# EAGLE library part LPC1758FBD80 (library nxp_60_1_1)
LPC1758 100 MHz 32-bit ARM Cortex-M3 based microcontroller featuring a high level of integration and low power consumption. 512 kB Flash, 64 kB SRAM, USB Device/Host/OTG, 2 CAN, DAC, Ethernet MarcVl - Datasheet available on www.nxp.com

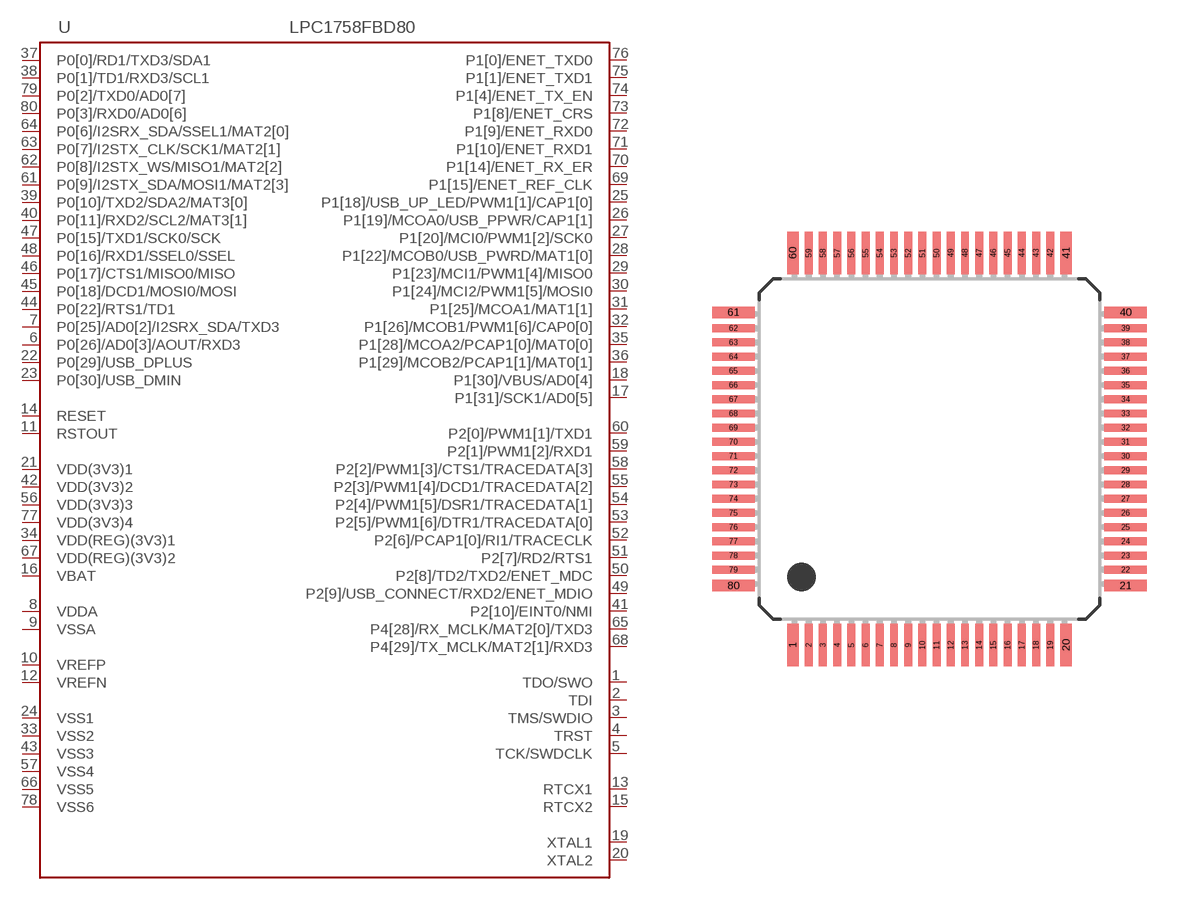
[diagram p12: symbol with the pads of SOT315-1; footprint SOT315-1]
Designator prefix U

## LPC1758FBD80  [SOT315-1]
1  TDO/SWO  out
2  TDI  in
3  TMS/SWDIO
4  TRST
5  TCK/SWDCLK
6  P0[26]/AD0[3]/AOUT/RXD3
7  P0[25]/AD0[2]/I2SRX_SDA/TXD3
8  VDDA  pwr
9  VSSA  pwr
10  VREFP  in
11  RSTOUT  out
12  VREFN  in
13  RTCX1  in
14  RESET  in
15  RTCX2  out
16  VBAT  pwr
17  P1[31]/SCK1/AD0[5]
18  P1[30]/VBUS/AD0[4]
19  XTAL1  in
20  XTAL2  out
21  VDD(3V3)1  pwr
22  P0[29]/USB_DPLUS
23  P0[30]/USB_DMIN
24  VSS1  pwr
25  P1[18]/USB_UP_LED/PWM1[1]/CAP1[0]
26  P1[19]/MCOA0/USB_PPWR/CAP1[1]
27  P1[20]/MCI0/PWM1[2]/SCK0
28  P1[22]/MCOB0/USB_PWRD/MAT1[0]
29  P1[23]/MCI1/PWM1[4]/MISO0
30  P1[24]/MCI2/PWM1[5]/MOSI0
31  P1[25]/MCOA1/MAT1[1]
32  P1[26]/MCOB1/PWM1[6]/CAP0[0]
33  VSS2  pwr
34  VDD(REG)(3V3)1  pwr
35  P1[28]/MCOA2/PCAP1[0]/MAT0[0]
36  P1[29]/MCOB2/PCAP1[1]/MAT0[1]
37  P0[0]/RD1/TXD3/SDA1
38  P0[1]/TD1/RXD3/SCL1
39  P0[10]/TXD2/SDA2/MAT3[0]
40  P0[11]/RXD2/SCL2/MAT3[1]
41  P2[10]/EINT0/NMI
42  VDD(3V3)2  pwr
43  VSS3  pwr
44  P0[22]/RTS1/TD1
45  P0[18]/DCD1/MOSI0/MOSI
46  P0[17]/CTS1/MISO0/MISO
47  P0[15]/TXD1/SCK0/SCK
48  P0[16]/RXD1/SSEL0/SSEL
49  P2[9]/USB_CONNECT/RXD2/ENET_MDIO
50  P2[8]/TD2/TXD2/ENET_MDC
51  P2[7]/RD2/RTS1
52  P2[6]/PCAP1[0]/RI1/TRACECLK
53  P2[5]/PWM1[6]/DTR1/TRACEDATA[0]
54  P2[4]/PWM1[5]/DSR1/TRACEDATA[1]
55  P2[3]/PWM1[4]/DCD1/TRACEDATA[2]
56  VDD(3V3)3  pwr
57  VSS4  pwr
58  P2[2]/PWM1[3]/CTS1/TRACEDATA[3]
59  P2[1]/PWM1[2]/RXD1
60  P2[0]/PWM1[1]/TXD1
61  P0[9]/I2STX_SDA/MOSI1/MAT2[3]
62  P0[8]/I2STX_WS/MISO1/MAT2[2]
63  P0[7]/I2STX_CLK/SCK1/MAT2[1]
64  P0[6]/I2SRX_SDA/SSEL1/MAT2[0]
65  P4[28]/RX_MCLK/MAT2[0]/TXD3
66  VSS5  pwr
67  VDD(REG)(3V3)2  pwr
68  P4[29]/TX_MCLK/MAT2[1]/RXD3
69  P1[15]/ENET_REF_CLK
70  P1[14]/ENET_RX_ER
71  P1[10]/ENET_RXD1
72  P1[9]/ENET_RXD0
73  P1[8]/ENET_CRS
74  P1[4]/ENET_TX_EN
75  P1[1]/ENET_TXD1
76  P1[0]/ENET_TXD0
77  VDD(3V3)4  pwr
78  VSS6  pwr
79  P0[2]/TXD0/AD0[7]
80  P0[3]/RXD0/AD0[6]

## Footprint SOT315-1 (pad centres in mm)
SOT315-1 LQFP80: plastic low profile quad flat package; 80 leads; body 12 x 12 x 1.4 mm JEDEC: MS-026 IEC: 136E15
smd 0.4 x 1.5: 1 -4.81,-6.9; 20 4.81,-6.9; 41 4.81,6.9; 60 -4.81,6.9
smd 0.28 x 1.5: 2 -4.25,-6.9; 3 -3.75,-6.9; 4 -3.25,-6.9; 5 -2.75,-6.9; 6 -2.25,-6.9; 7 -1.75,-6.9; 8 -1.25,-6.9; 9 -0.75,-6.9; 10 -0.25,-6.9; 11 0.25,-6.9; 12 0.75,-6.9; 13 1.25,-6.9; 14 1.75,-6.9; 15 2.25,-6.9; 16 2.75,-6.9; 17 3.25,-6.9; 18 3.75,-6.9; 19 4.25,-6.9; 42 4.25,6.9; 43 3.75,6.9; 44 3.25,6.9; 45 2.75,6.9; 46 2.25,6.9; 47 1.75,6.9; 48 1.25,6.9; 49 0.75,6.9; 50 0.25,6.9; 51 -0.25,6.9; 52 -0.75,6.9; 53 -1.25,6.9; 54 -1.75,6.9; 55 -2.25,6.9; 56 -2.75,6.9; 57 -3.25,6.9; 58 -3.75,6.9; 59 -4.25,6.9
smd 1.5 x 0.4: 21 6.9,-4.81; 40 6.9,4.81; 61 -6.9,4.81; 80 -6.9,-4.81
smd 1.5 x 0.28: 22 6.9,-4.25; 23 6.9,-3.75; 24 6.9,-3.25; 25 6.9,-2.75; 26 6.9,-2.25; 27 6.9,-1.75; 28 6.9,-1.25; 29 6.9,-0.75; 30 6.9,-0.25; 31 6.9,0.25; 32 6.9,0.75; 33 6.9,1.25; 34 6.9,1.75; 35 6.9,2.25; 36 6.9,2.75; 37 6.9,3.25; 38 6.9,3.75; 39 6.9,4.25; 62 -6.9,4.25; 63 -6.9,3.75; 64 -6.9,3.25; 65 -6.9,2.75; 66 -6.9,2.25; 67 -6.9,1.75; 68 -6.9,1.25; 69 -6.9,0.75; 70 -6.9,0.25; 71 -6.9,-0.25; 72 -6.9,-0.75; 73 -6.9,-1.25; 74 -6.9,-1.75; 75 -6.9,-2.25; 76 -6.9,-2.75; 77 -6.9,-3.25; 78 -6.9,-3.75; 79 -6.9,-4.25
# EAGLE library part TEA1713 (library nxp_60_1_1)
Resonant power supply control IC with PFC. AAL Eindhoven MK

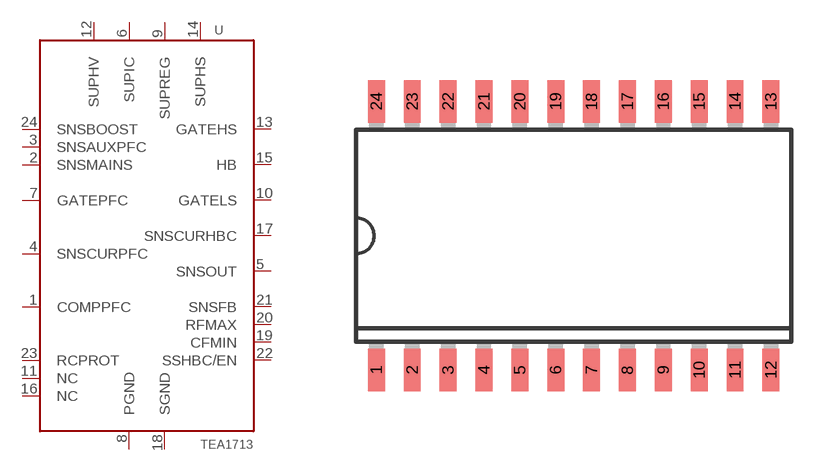
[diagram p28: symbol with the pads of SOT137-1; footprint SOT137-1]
Designator prefix U

## TEA1713T (12NC: 9352 895 98518; FARNELL: 1872212)  [SOT137-1]
1  COMPPFC  pas
2  SNSMAINS  pas
3  SNSAUXPFC  pas
4  SNSCURPFC  pas
5  SNSOUT  out
6  SUPIC  pwr
7  GATEPFC  out
8  PGND  pwr
9  SUPREG  pas
10  GATELS  out
11  NC  out
12  SUPHV  in
13  GATEHS  out
14  SUPHS  in
15  HB  in
16  NC  out
17  SNSCURHBC  out
18  SGND  pwr
19  CFMIN  pas
20  RFMAX  pas
21  SNSFB  in
22  SSHBC/EN  in
23  RCPROT  pas
24  SNSBOOST  in

## Footprint SOT137-1 (pad centres in mm)
SOT137-1 SO24: plastic small outline package; 24 leads; body width 7.5 mm JEDEC: MS-013 IEC: 075E05
smd 0.6 x 1.5: 1 -6.985,-4.75; 2 -5.715,-4.75; 3 -4.445,-4.75; 4 -3.175,-4.75; 5 -1.905,-4.75; 6 -0.635,-4.75; 7 0.635,-4.75; 8 1.905,-4.75; 9 3.175,-4.75; 10 4.445,-4.75; 11 5.715,-4.75; 12 6.985,-4.75; 13 6.985,4.75; 14 5.715,4.75; 15 4.445,4.75; 16 3.175,4.75; 17 1.905,4.75; 18 0.635,4.75; 19 -0.635,4.75; 20 -1.905,4.75; 21 -3.175,4.75; 22 -4.445,4.75; 23 -5.715,4.75; 24 -6.985,4.75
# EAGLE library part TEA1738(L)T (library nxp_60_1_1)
The TEA1738(T) is a low cost Switched Mode Power Supply (SMPS) controller IC intended for flyback topologies. The TEA1738(T) operates in peak current and frequency control mode. To reduce Electro Magnetic Interference (EMI), frequency jitter has been implemented. Slope compensation is integrated for Continuous Conduction Mode (CCM) operation. AAL Eindhoven MK

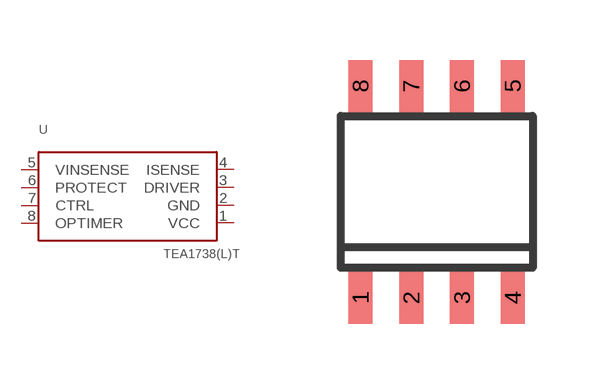
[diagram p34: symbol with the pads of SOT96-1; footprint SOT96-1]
Designator prefix U

## TEA1738(L)T (12NC: 9352 918 76118)  [SOT96-1]
1  VCC  pwr
2  GND  pwr
3  DRIVER  out
4  ISENSE  in
5  VINSENSE  in
6  PROTECT  in
7  CTRL  in
8  OPTIMER  pas

## Footprint SOT96-1 (pad centres in mm)
SOT96-1 SO8: plastic small outline package; 8 leads; body width 3.9 mm JEDEC: MS-012 IEC: 076E03
smd 0.6 x 1.3: 1 -1.905,-2.65; 2 -0.635,-2.65; 3 0.635,-2.65; 4 1.905,-2.65; 5 1.905,2.65; 6 0.635,2.65; 7 -0.635,2.65; 8 -1.905,2.65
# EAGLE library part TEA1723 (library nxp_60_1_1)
Switch mode power supply controller AAL Eindhoven MK

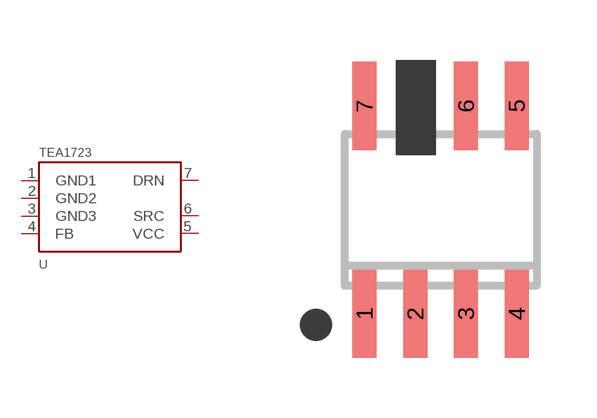
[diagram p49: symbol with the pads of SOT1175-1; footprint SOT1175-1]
Designator prefix U

## TEA1723 (12NC: 9352 968 88118)  [SOT1175-1]
1  GND1  pwr
2  GND2  pwr
3  GND3  pwr
4  FB
5  VCC  pwr
6  SRC  in
7  DRN  out

## Footprint SOT1175-1 (pad centres in mm)
SOT1175-1 SO7: plastic small outline package; 7 leads; body width 3.9 m JEDEC: --- IEC: ---
smd 0.6 x 2.2: 1 -1.905,-2.6; 2 -0.635,-2.6; 3 0.635,-2.6; 4 1.905,-2.6; 5 1.905,2.6; 6 0.635,2.6; 7 -1.905,2.6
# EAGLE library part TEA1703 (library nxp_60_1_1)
GreenChip SMPS standby control IC

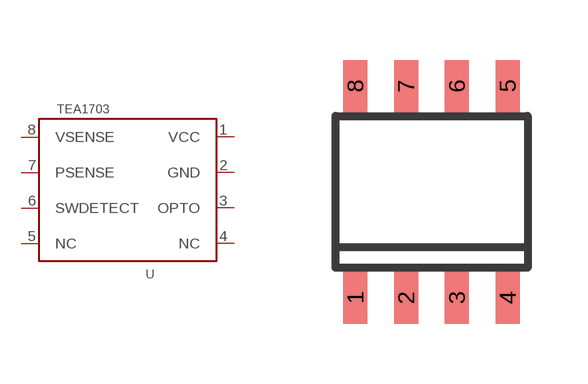
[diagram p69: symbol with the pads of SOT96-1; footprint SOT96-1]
Designator prefix U

## TEA1703  [SOT96-1]
1  VCC  pwr
2  GND  pwr
3  OPTO  out
4  NC  in
5  NC  in
6  SWDETECT  pas
7  PSENSE  pas
8  VSENSE  pas

## Footprint SOT96-1 (pad centres in mm)
SOT96-1 SO8: plastic small outline package; 8 leads; body width 3.9 mm JEDEC: MS-012 IEC: 076E03
smd 0.6 x 1.3: 1 -1.905,-2.65; 2 -0.635,-2.65; 3 0.635,-2.65; 4 1.905,-2.65; 5 1.905,2.65; 6 0.635,2.65; 7 -0.635,2.65; 8 -1.905,2.65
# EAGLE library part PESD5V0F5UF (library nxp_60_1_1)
Femtofarad unidirectional fivefold ESD protection array Femtofarad capacitance unidirectional ElectroStatic Discharge (ESD) protection diode array designed to protect up to five signal lines from the damage caused by ESD and other transients. The device is encapsulated in a leadless ultra small DFN1410-6 (SOT886) Surface-Mounted Device (SMD) plastic package. The combination of extremely low capacitance, high ESD maximum rating and ultra small package makes the device ideal for high-speed data line protection and antenna protection applications. AAL Eindhoven MK

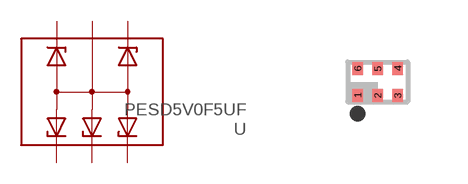
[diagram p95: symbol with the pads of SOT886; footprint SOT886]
Designator prefix U

## PESD5V0F5UF  [SOT886]
1  1  pas
2  2  pas
3  3  pas
4  4  pas
5  5  pas
6  6  pas

## Footprint SOT886 (pad centres in mm)
SOT886 XSON6: plastic extremely thin small outline package; no leads; 6 terminals; body 1 x 1.45 x 0.5 mm JEDEC: MO-252 IEC: ---
smd 0.27 x 0.325: 1 -0.5,-0.338; 2 0,-0.338; 3 0.5,-0.338; 4 0.5,0.338; 5 0,0.338; 6 -0.5,0.338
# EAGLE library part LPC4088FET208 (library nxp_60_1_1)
32-bit ARM Cortex-M4 MCU; up to 512 kB flash, 96 kB SRAM; USB Device/Host/OTG; Ethernet; LCD; EMC; SPIFI The LPC408x/7x is an ARM Cortex-M4 based digital signal controller for embedded applications requiring a high level of integration and low power dissipation. The ARM Cortex-M4 is a next generation core that offers system enhancements such as low power consumption, enhanced debug features, and a high level of support block integration. The ARM Cortex-M4 CPU incorporates a 3-stage pipeline, uses a Harvard architecture with separate local instruction and data buses as well as a third bus for peripherals, and includes an internal prefetch unit that supports speculative branching. The ARM Cortex-M4 supports single-cycle digital signal processing and SIMD instructions. A hardware floating-point processor is integrated in the core for several versions of the part. The LPC408x/7x adds a specialized flash memory accelerator to accomplish optimal performance when executing code from flash. The LPC408x/7x is targeted to operate at up to 120 MHz CPU frequency. The peripheral complement of the LPC408x/7x includes up to 512 kB of flash program memory, up to 96 kB of SRAM data memory, up to 4032 byte of EEPROM data memory, External Memory controller (EMC), LCD, Ethernet, USB Device/Host/OTG, an SPI Flash Interface (SPIFI), a General Purpose DMA controller, five UARTs, three SSP controllers, three I 2 C-bus interfaces, a Quadrature Encoder Interface, four general purpose timers, two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

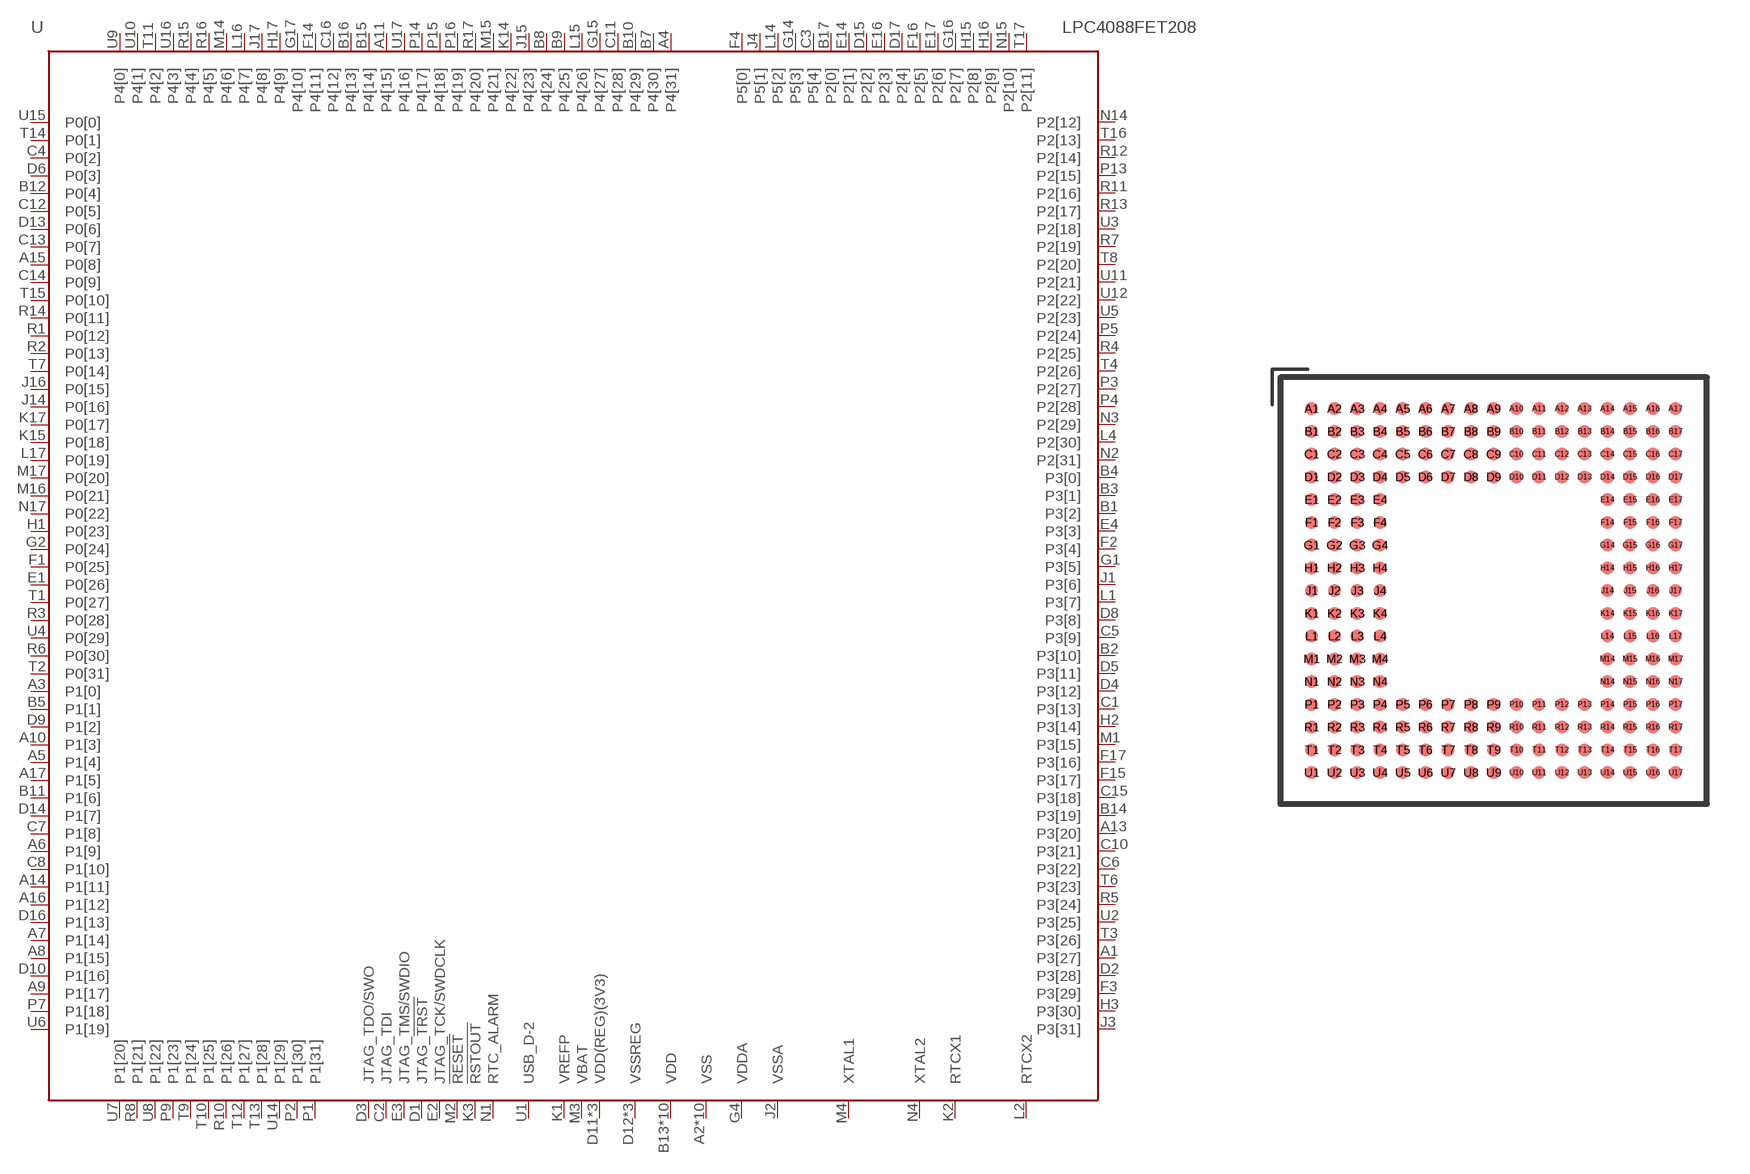
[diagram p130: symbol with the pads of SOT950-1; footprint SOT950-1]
Designator prefix U

## LPC4088FET208  [SOT950-1]
A1  P3[27]
A2  VSS  pwr
A3  P1[0]
A4  P4[31]
A5  P1[4]
A6  P1[9]
A7  P1[14]
A8  P1[15]
A9  P1[17]
A10  P1[3]
A11  P4[15]
A12  VSS  pwr
A13  P3[20]
A14  P1[11]
A15  P0[8]
A16  P1[12]
A17  P1[5]
B1  P3[2]
B2  P3[10]
B3  P3[1]
B4  P3[0]
B5  P1[1]
B6  VSS  pwr
B7  P4[30]
B8  P4[24]
B9  P4[25]
B10  P4[29]
B11  P1[6]
B12  P0[4]
B13  VDD  pwr
B14  P3[19]
B15  P4[14]
B16  P4[13]
B17  P2[0]
C1  P3[13]
C2  JTAG_TDI  in
C3  P5[4]
C4  P0[2]
C5  P3[9]
C6  P3[22]
C7  P1[8]
C8  P1[10]
C9  VDD  pwr
C10  P3[21]
C11  P4[28]
C12  P0[5]
C13  P0[7]
C14  P0[9]
C15  P3[18]
C16  P4[12]
C17  VDD  pwr
D1  JTAG_!TRST  in
D2  P3[28]
D3  JTAG_TDO/SWO  out
D4  P3[12]
D5  P3[11]
D6  P0[3]
D7  VDD  pwr
D8  P3[8]
D9  P1[2]
D10  P1[16]
D11  VDD(REG)(3V3)  pwr
D12  VSSREG  pwr
D13  P0[6]
D14  P1[7]
D15  P2[2]
D16  P1[13]
D17  P2[4]
E1  P0[26]
E2  JTAG_TCK/SWDCLK  in
E3  JTAG_TMS/SWDIO  in
E4  P3[3]
E14  P2[1]
E15  VSS  pwr
E16  P2[3]
E17  P2[6]
F1  P0[25]
F2  P3[4]
F3  P3[29]
F4  P5[0]
F14  P4[11]
F15  P3[17]
F16  P2[5]
F17  P3[16]
G1  P3[5]
G2  P0[24]
G3  VDD  pwr
G4  VDDA  pwr
G14  P5[3]
G15  P4[27]
G16  P2[7]
G17  P4[10]
H1  P0[23]
H2  P3[14]
H3  P3[30]
H4  VDD(REG)(3V3)  pwr
H14  VSS  pwr
H15  P2[8]
H16  P2[9]
H17  P4[9]
J1  P3[6]
J2  VSSA  pwr
J3  P3[31]
J4  P5[1]
J14  P0[16]
J15  P4[23]
J16  P0[15]
J17  P4[8]
K1  VREFP  pwr
K2  RTCX1  in
K3  !RSTOUT!  out
K4  VSSREG  pwr
K14  P4[22]
K15  P0[18]
K16  VDD  pwr
K17  P0[17]
L1  P3[7]
L2  RTCX2  out
L3  VSS  pwr
L4  P2[30]
L14  P5[2]
L15  P4[26]
L16  P4[7]
L17  P0[19]
M1  P3[15]
M2  !RESET!  in
M3  VBAT  pwr
M4  XTAL1  in
M14  P4[6]
M15  P4[21]
M16  P0[21]
M17  P0[20]
N1  RTC_ALARM  out
N2  P2[31]
N3  P2[29]
N4  XTAL2  out
N14  P2[12]
N15  P2[10]
N16  VSS  pwr
N17  P0[22]
P1  P1[31]
P2  P1[30]
P3  P2[27]
P4  P2[28]
P5  P2[24]
P6  VDD  pwr
P7  P1[18]
P8  VDD  pwr
P9  P1[23]
P10  VSSREG  pwr
P11  VDD(REG)(3V3)  pwr
P12  VSS  pwr
P13  P2[15]
P14  P4[17]
P15  P4[18]
P16  P4[19]
P17  VDD  pwr
R1  P0[12]
R2  P0[13]
R3  P0[28]
R4  P2[25]
R5  P3[24]
R6  P0[30]
R7  P2[19]
R8  P1[21]
R9  VSS  pwr
R10  P1[26]
R11  P2[16]
R12  P2[14]
R13  P2[17]
R14  P0[11]
R15  P4[4]
R16  P4[5]
R17  P4[20]
T1  P0[27]
T2  P0[31]
T3  P3[26]
T4  P2[26]
T5  VSS  pwr
T6  P3[23]
T7  P0[14]
T8  P2[20]
T9  P1[24]
T10  P1[25]
T11  P4[2]
T12  P1[27]
T13  P1[28]
T14  P0[1]
T15  P0[10]
T16  P2[13]
T17  P2[11]
U1  USB_D-2
U2  P3[25]
U3  P2[18]
U4  P0[29]
U5  P2[23]
U6  P1[19]
U7  P1[20]
U8  P1[22]
U9  P4[0]
U10  P4[1]
U11  P2[21]
U12  P2[22]
U13  VDD  pwr
U14  P1[29]
U15  P0[0]
U16  P4[3]
U17  P4[16]

## Footprint SOT950-1 (pad centres in mm)
SOT950-1 TFBGA208: plastic thin fine-pitch ball grid array package; 208 balls; body 15 x 15 x 0.7 mm JEDEC: -- IEC: -- JEITA: -- Shamelessly copied from nxp_packages.lbr
smd 0.45 x 0.45: A1 -6.4,6.4; A2 -5.6,6.4; A3 -4.8,6.4; A4 -4,6.4; A5 -3.2,6.4; A6 -2.4,6.4; A7 -1.6,6.4; A8 -0.8,6.4; A9 0,6.4; A10 0.8,6.4; A11 1.6,6.4; A12 2.4,6.4; A13 3.2,6.4; A14 4,6.4; A15 4.8,6.4; A16 5.6,6.4; A17 6.4,6.4; B1 -6.4,5.6; B2 -5.6,5.6; B3 -4.8,5.6; B4 -4,5.6; B5 -3.2,5.6; B6 -2.4,5.6; B7 -1.6,5.6; B8 -0.8,5.6; B9 0,5.6; B10 0.8,5.6; B11 1.6,5.6; B12 2.4,5.6; B13 3.2,5.6; B14 4,5.6; B15 4.8,5.6; B16 5.6,5.6; B17 6.4,5.6; C1 -6.4,4.8; C2 -5.6,4.8; C3 -4.8,4.8; C4 -4,4.8; C5 -3.2,4.8; C6 -2.4,4.8; C7 -1.6,4.8; C8 -0.8,4.8; C9 0,4.8; C10 0.8,4.8; C11 1.6,4.8; C12 2.4,4.8; C13 3.2,4.8; C14 4,4.8; C15 4.8,4.8; C16 5.6,4.8; C17 6.4,4.8; D1 -6.4,4; D2 -5.6,4; D3 -4.8,4; D4 -4,4; D5 -3.2,4; D6 -2.4,4; D7 -1.6,4; D8 -0.8,4; D9 0,4; D10 0.8,4; D11 1.6,4; D12 2.4,4; D13 3.2,4; D14 4,4; D15 4.8,4; D16 5.6,4; D17 6.4,4; E1 -6.4,3.2; E2 -5.6,3.2; E3 -4.8,3.2; E4 -4,3.2; E14 4,3.2; E15 4.8,3.2; E16 5.6,3.2; E17 6.4,3.2; F1 -6.4,2.4; F2 -5.6,2.4; F3 -4.8,2.4; F4 -4,2.4; F14 4,2.4; F15 4.8,2.4; F16 5.6,2.4; F17 6.4,2.4; G1 -6.4,1.6; G2 -5.6,1.6; G3 -4.8,1.6; G4 -4,1.6; G14 4,1.6; G15 4.8,1.6; G16 5.6,1.6; G17 6.4,1.6; H1 -6.4,0.8; H2 -5.6,0.8; H3 -4.8,0.8; H4 -4,0.8; H14 4,0.8; H15 4.8,0.8; H16 5.6,0.8; H17 6.4,0.8; J1 -6.4,0; J2 -5.6,0; J3 -4.8,0; J4 -4,0; J14 4,0; J15 4.8,0; J16 5.6,0; J17 6.4,0; K1 -6.4,-0.8; K2 -5.6,-0.8; K3 -4.8,-0.8; K4 -4,-0.8; K14 4,-0.8; K15 4.8,-0.8; K16 5.6,-0.8; K17 6.4,-0.8; L1 -6.4,-1.6; L2 -5.6,-1.6; L3 -4.8,-1.6; L4 -4,-1.6; L14 4,-1.6; L15 4.8,-1.6; L16 5.6,-1.6; L17 6.4,-1.6; M1 -6.4,-2.4; M2 -5.6,-2.4; M3 -4.8,-2.4; M4 -4,-2.4; M14 4,-2.4; M15 4.8,-2.4; M16 5.6,-2.4; M17 6.4,-2.4; N1 -6.4,-3.2; N2 -5.6,-3.2; N3 -4.8,-3.2; N4 -4,-3.2; N14 4,-3.2; N15 4.8,-3.2; N16 5.6,-3.2; N17 6.4,-3.2; P1 -6.4,-4; P2 -5.6,-4; P3 -4.8,-4; P4 -4,-4; P5 -3.2,-4; P6 -2.4,-4; P7 -1.6,-4; P8 -0.8,-4; P9 0,-4; P10 0.8,-4; P11 1.6,-4; P12 2.4,-4; P13 3.2,-4; P14 4,-4; P15 4.8,-4; P16 5.6,-4; P17 6.4,-4; R1 -6.4,-4.8; R2 -5.6,-4.8; R3 -4.8,-4.8; R4 -4,-4.8; R5 -3.2,-4.8; R6 -2.4,-4.8; R7 -1.6,-4.8; R8 -0.8,-4.8; R9 0,-4.8; R10 0.8,-4.8; R11 1.6,-4.8; R12 2.4,-4.8; R13 3.2,-4.8; R14 4,-4.8; R15 4.8,-4.8; R16 5.6,-4.8; R17 6.4,-4.8; T1 -6.4,-5.6; T2 -5.6,-5.6; T3 -4.8,-5.6; T4 -4,-5.6; T5 -3.2,-5.6; T6 -2.4,-5.6; T7 -1.6,-5.6; T8 -0.8,-5.6; T9 0,-5.6; T10 0.8,-5.6; T11 1.6,-5.6; T12 2.4,-5.6; T13 3.2,-5.6; T14 4,-5.6; T15 4.8,-5.6; T16 5.6,-5.6; T17 6.4,-5.6; U1 -6.4,-6.4; U2 -5.6,-6.4; U3 -4.8,-6.4; U4 -4,-6.4; U5 -3.2,-6.4; U6 -2.4,-6.4; U7 -1.6,-6.4; U8 -0.8,-6.4; U9 0,-6.4; U10 0.8,-6.4; U11 1.6,-6.4; U12 2.4,-6.4; U13 3.2,-6.4; U14 4,-6.4; U15 4.8,-6.4; U16 5.6,-6.4; U17 6.4,-6.4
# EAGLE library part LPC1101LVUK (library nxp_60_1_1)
32-bit ARM Cortex-M0 MCU; up to 32 kB flash, 8 kB SRAM; 8-bit ADC The LPC111xLV/LPC11xxLVUK is an ARM Cortex-M0-based, low-cost 32-bit MCU family, designed for 8/16-bit microcontroller applications, offering performance, low power, simple instruction set and memory addressing together with reduced code size compared to existing 8/16-bit architectures. The LPC111xLV/LPC11xxLVUK operate at CPU frequencies of up to 50 MHz. The peripherals of the LPC111xLV/LPC11xxLVUK include up to 32 kB of flash memory, up to 8 kB of SRAM data memory, a Fast-mode Plus I 2 C-bus interface, one SSP/SPI interface, one UART, four general-purpose counter/timers, an 8-bit ADC, and up to 27 general-purpose I/O pins. AAL Eindhoven MK

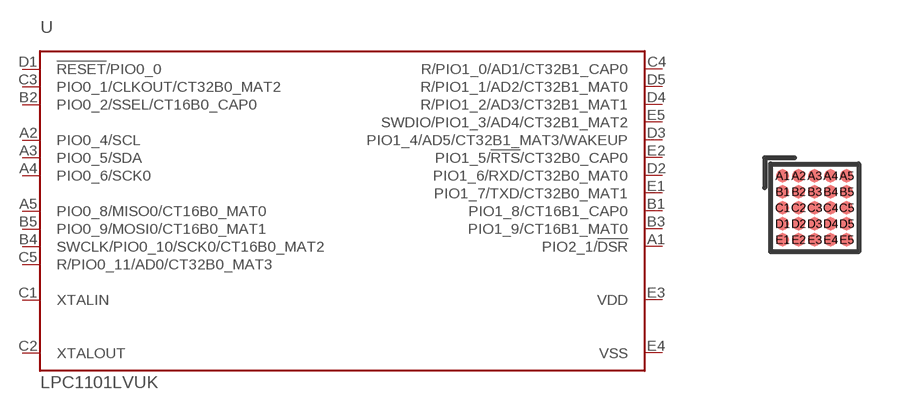
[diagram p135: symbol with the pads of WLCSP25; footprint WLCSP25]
Designator prefix U

## LPC1101LVUK  [WLCSP25]
A1  PIO2_1/!DSR!
A2  PIO0_4/SCL
A3  PIO0_5/SDA
A4  PIO0_6/SCK0
A5  PIO0_8/MISO0/CT16B0_MAT0
B1  PIO1_8/CT16B1_CAP0
B2  PIO0_2/SSEL/CT16B0_CAP0
B3  PIO1_9/CT16B1_MAT0
B4  SWCLK/PIO0_10/SCK0/CT16B0_MAT2
B5  PIO0_9/MOSI0/CT16B0_MAT1
C1  XTALIN  in
C2  XTALOUT  out
C3  PIO0_1/CLKOUT/CT32B0_MAT2
C4  R/PIO1_0/AD1/CT32B1_CAP0
C5  R/PIO0_11/AD0/CT32B0_MAT3
D1  !RESET!/PIO0_0
D2  PIO1_6/RXD/CT32B0_MAT0
D3  PIO1_4/AD5/CT32B1_MAT3/WAKEUP
D4  R/PIO1_2/AD3/CT32B1_MAT1
D5  R/PIO1_1/AD2/CT32B1_MAT0
E1  PIO1_7/TXD/CT32B0_MAT1
E2  PIO1_5/!RTS!/CT32B0_CAP0
E3  VDD  pwr
E4  VSS  pwr
E5  SWDIO/PIO1_3/AD4/CT32B1_MAT2

## Footprint WLCSP25 (pad centres in mm)
WLCSP25 Wafer level chip-size package; 25 bumps (5 x 5) JEDEC: -- IEC: -- JEITA: -- Shamelessly copied from nxp_packages.lbr
smd 0.32 x 0.32: A1 -0.8,0.8; A2 -0.4,0.8; A3 0,0.8; A4 0.4,0.8; A5 0.8,0.8; B1 -0.8,0.4; B2 -0.4,0.4; B3 0,0.4; B4 0.4,0.4; B5 0.8,0.4; C1 -0.8,0; C2 -0.4,0; C3 0,0; C4 0.4,0; C5 0.8,0; D1 -0.8,-0.4; D2 -0.4,-0.4; D3 0,-0.4; D4 0.4,-0.4; D5 0.8,-0.4; E1 -0.8,-0.8; E2 -0.4,-0.8; E3 0,-0.8; E4 0.4,-0.8; E5 0.8,-0.8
